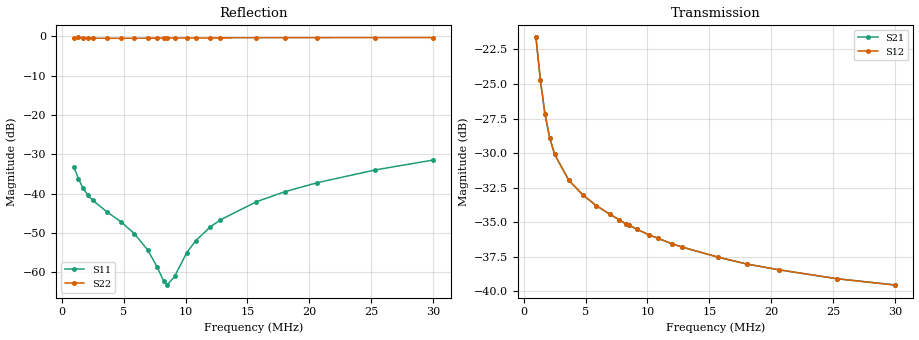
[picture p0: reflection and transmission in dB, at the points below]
! ListType=Log
!!FT140-43 7T
# MHZ S RI R 50
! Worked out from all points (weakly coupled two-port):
!   101 points, 1 MHz to 30 MHz, reference 50 ohm
!   highest |S21| = -21.63 dB at 1 MHz (marker M1); lowest = -39.5 dB at 30 MHz (marker M2)
!   lowest |S11| = -63.2 dB at 8.523 MHz (marker M3), VSWR 1.00, Z = 50.1 + j0.045 ohm
!   |S11| at or under -10 dB: start of sweep to end of sweep
!   |S22| runs from -0.5 to -0.3 dB; largest |S21 - S12| = 3.1e-05
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1  -0.00639 0.0208  0.0226 -0.0797  0.0226 -0.0797  0.9102 0.3178
1.358129  -0.00409 0.0149  0.0146 -0.0563  0.0146 -0.0563  0.942 0.2233
1.723215  -0.00349 0.0113  0.0134 -0.0418  0.0134 -0.0418  0.9469 0.1643
2.113327  -0.00339 0.00903  0.014 -0.033  0.014 -0.033  0.9445 0.1282
2.505087  -0.00323 0.0076  0.0146 -0.0277  0.0146 -0.0277  0.9419 0.1059
3.641716  -0.00267 0.00527  0.0153 -0.0201  0.0153 -0.0201  0.9391 0.0732
4.780527  -0.00198 0.00394  0.015 -0.0166  0.0149 -0.0166  0.9406 0.0572
5.862773  -0.00121 0.00287  0.0143 -0.0146  0.0143 -0.0146  0.943 0.0469
6.949589  -0.000507 0.00186  0.0137 -0.0132  0.0137 -0.0132  0.9456 0.0389
7.696136  9.8e-06 0.00118  0.0133 -0.0124  0.0133 -0.0124  0.9472 0.0341
8.237875  0.00036 0.000692  0.013 -0.0118  0.013 -0.0118  0.9483 0.031
8.52288  0.000522 0.000449  0.0129 -0.0116  0.0129 -0.0116  0.9488 0.0293
9.122814  0.00089 -7.3e-05  0.0126 -0.0111  0.0126 -0.0111  0.9499 0.0262
10.10282  0.0015 -0.000957  0.0122 -0.0104  0.0122 -0.0104  0.9514 0.0213
10.81396  0.00194 -0.0016  0.012 -0.00994  0.012 -0.00994  0.9524 0.0181
11.97563  0.00261 -0.0027  0.0116 -0.00929  0.0116 -0.0093  0.9538 0.0132
12.81861  0.00308 -0.00348  0.0114 -0.00888  0.0114 -0.00889  0.9546 0.00979
15.72057  0.00469 -0.00634  0.0108 -0.00774  0.0108 -0.00775  0.957 -0.000653
18.01163  0.00595 -0.00876  0.0104 -0.00704  0.0104 -0.00705  0.9585 -0.00802
20.63659  0.0073 -0.0117  0.0101 -0.00641  0.0101 -0.00642  0.9596 -0.0159
25.30843  0.00958 -0.0176  0.00963 -0.00555  0.00962 -0.00556  0.961 -0.0289
30  0.0115 -0.0242  0.00934 -0.00491  0.00932 -0.00492  0.9619 -0.0409
